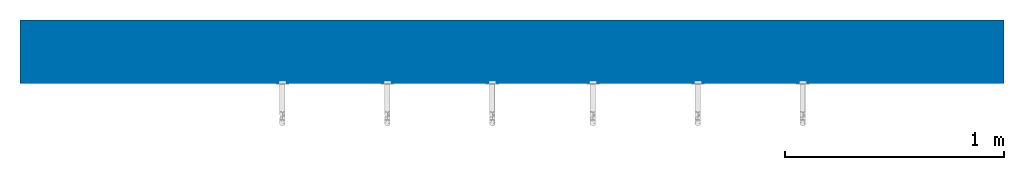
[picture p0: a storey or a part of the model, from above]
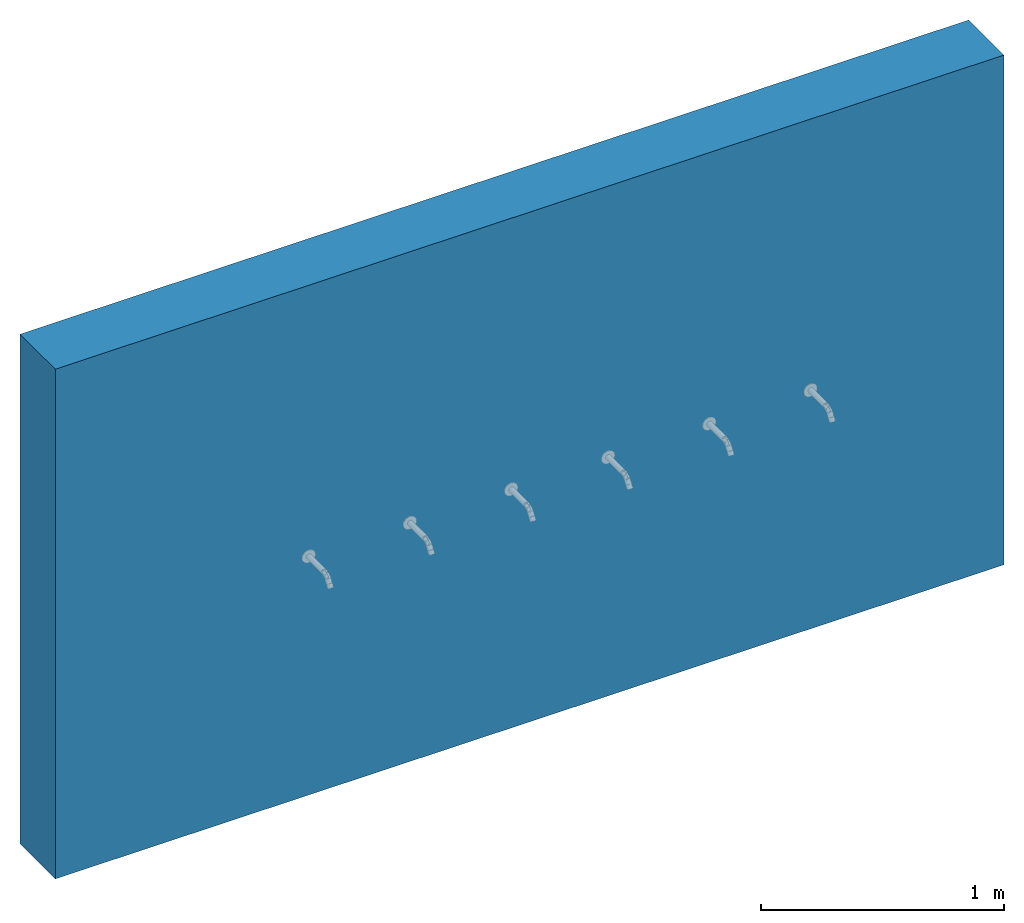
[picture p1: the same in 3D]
Properties of the parts of a building model (IFC2X3)

# File
Description: ViewDefinition [CoordinationView_V2.0]
File name: Project Number
Time: 2021-09-14T16:37:05
Written by: The EXPRESS Data Manager Version 5.02.0100.07 : 28 Aug 2013
Made in: 20190808_0900(x64) - Exporter 19.2.20.24 - Alternate UI 19.2.20.24
Comment: STEP Physical File produced by: The EXPRESS Data Manager Version 5.02.0100.07 : 28 Aug 2013 * Module: EDMstepFileFactory/EDMstandAlone * Creation date: Tue Sep 14 16:37:05 2021 * Host: DESKTOP-KN3O7NT * Database: C:\Users\SARAHS~1\AppData\Local\Temp\{A5B28278-2AD7-4449-B1EB-ECA2539A65EE}\ifc * Database version: 5507 * Database creation date: Tue Sep 14 16:37:03 2021 * Schema: IFC2X3 * Model: DataRepository.ifc * Model creation date: Tue Sep 14 16:37:04 2021 * Header model: DataRepository.ifc_HeaderModel * Header model creation date: Tue Sep 14 16:37:04 2021 * EDMuser: sdai-user * EDMgroup: sdai-group * License ID and type: 5605 : Permanent license. Expiry date: * EDMstepFileFactory options: 020000

# IfcProject, Project Number
LongName: Project Name; Phase: Project Status

# IfcSite, Default
RefLatitude: 51, 30, 23, 112487; RefLongitude: 0, -7, -37, -956022; RefElevation: 0 mm

# IfcBuilding
Pset_BuildingCommon - NumberOfStoreys: 1

# IfcBuildingStorey, Level 0
LongName: Level 0; Elevation: 0 mm

# IfcFlowController: Recessed Installation Battery Pack Brushed Stainless Steel, Duten_WtrSplyFitngsForWshBsnsAndTrghs_R335-TR:Recessed Installation Battery Pack Brushed Stainless Steel:314117
In: Level 0
Type - PredefinedType: FAUCET; Classification: C1030210 Bath & Toilet Accessories - Commercial (Uniformat); Material: Duten_Metal_BrushedStainlessSteel, Duten_Plastic_Black
Pset_ManufacturerTypeInformation - ModelReference: Recessed Installation Battery Pack Brushed Stainless Steel; Manufacturer: Duten
Pset_DistributionFlowElementCommon - Reference: n/a

# IfcFlowController: Recessed Installation Battery Pack Matte Black, Duten_WtrSplyFitngsForWshBsnsAndTrghs_R335-TR:Recessed Installation Battery Pack Matte Black:314137
In: Level 0
Type - PredefinedType: FAUCET; Classification: C1030210 Bath & Toilet Accessories - Commercial (Uniformat); Material: Duten_Metal_MatteBlack, Duten_Plastic_Black
Pset_ManufacturerTypeInformation - ModelReference: Recessed Installation Battery Pack Matte Black; Manufacturer: Duten
Pset_DistributionFlowElementCommon - Reference: n/a

# IfcFlowController: Recessed Installation Battery Pack Polished Stainless Steel, Duten_WtrSplyFitngsForWshBsnsAndTrghs_R335-TR:Recessed Installation Battery Pack Polished Stainless Steel:314312
In: Level 0
Type - PredefinedType: FAUCET; Classification: C1030210 Bath & Toilet Accessories - Commercial (Uniformat); Material: Duten_Metal_Polished, Duten_Plastic_Black
Pset_ManufacturerTypeInformation - ModelReference: Recessed Installation Battery Pack Polished Stainless Steel; Manufacturer: Duten
Pset_DistributionFlowElementCommon - Reference: n/a

# IfcFlowController: Recessed Installation Transformer Brushed Stainless Steel, Duten_WtrSplyFitngsForWshBsnsAndTrghs_R335-TR:Recessed Installation Transformer Brushed Stainless Steel:315447
In: Level 0
Type - PredefinedType: FAUCET; Classification: C1030210 Bath & Toilet Accessories - Commercial (Uniformat); Material: Duten_Metal_BrushedStainlessSteel, Duten_Plastic_Black
Pset_ManufacturerTypeInformation - ModelReference: Recessed Installation Transformer Brushed Stainless Steel; Manufacturer: Duten
Pset_DistributionFlowElementCommon - Reference: n/a

# IfcFlowController: Recessed Installation Transformer Matte Black, Duten_WtrSplyFitngsForWshBsnsAndTrghs_R335-TR:Recessed Installation Transformer Matte Black:315449
In: Level 0
Type - PredefinedType: FAUCET; Classification: C1030210 Bath & Toilet Accessories - Commercial (Uniformat); Material: Duten_Metal_MatteBlack, Duten_Plastic_Black
Pset_ManufacturerTypeInformation - ModelReference: Recessed Installation Transformer Matte Black; Manufacturer: Duten
Pset_DistributionFlowElementCommon - Reference: n/a

# IfcFlowController: Recessed Installation Transformer Polished Stainless Steel, Duten_WtrSplyFitngsForWshBsnsAndTrghs_R335-TR:Recessed Installation Transformer Polished Stainless Steel:315450
In: Level 0
Type - PredefinedType: FAUCET; Classification: C1030210 Bath & Toilet Accessories - Commercial (Uniformat); Material: Duten_Metal_Polished, Duten_Plastic_Black
Pset_ManufacturerTypeInformation - ModelReference: Recessed Installation Transformer Polished Stainless Steel; Manufacturer: Duten
Pset_DistributionFlowElementCommon - Reference: n/a

# IfcWallStandardCase: Basic Wall:Wall-Ext_102Bwk-75Ins-100LBlk-12P, Basic Wall:Wall-Ext_102Bwk-75Ins-100LBlk-12P:313205
In: Level 0
Type - PredefinedType: STANDARD; Material: Brick, Common 102.5 mm, Fiberglass Batt 75 mm, Concrete Masonry Units _Low Density 100 mm, Plaster 12.5 mm
Pset_WallCommon - Reference: Wall-Ext_102Bwk-75Ins-100LBlk-12P; LoadBearing: no; ExtendToStructure: no; IsExternal: yes; ThermalTransmittance: 0.235926 kg/K/s3
